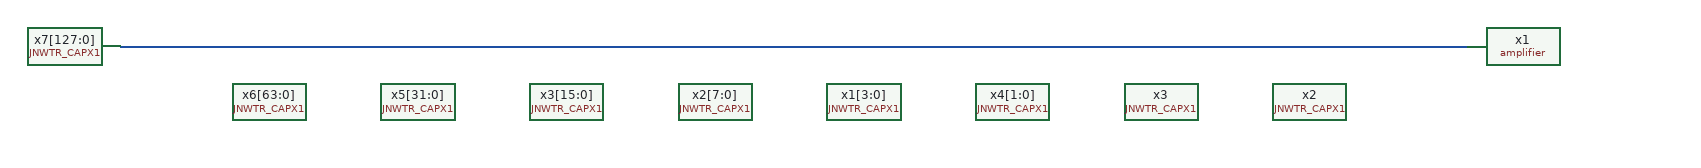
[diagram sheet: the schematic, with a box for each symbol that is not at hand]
v {xschem version=3.4.6 file_version=1.2}
G {}
K {}
V {}
S {}
E {}
N -860 -20 -700 -20 {lab=#net1}
N -700 -20 -540 -20 {lab=#net1}
N -540 -20 -380 -20 {lab=#net1}
N -380 -20 -220 -20 {lab=#net1}
N -220 -20 -60 -20 {lab=#net1}
N -60 -20 110 -20 {lab=#net1}
N -1340 -20 -1180 -20 {lab=#net1}
N -1180 -20 -1020 -20 {lab=#net1}
N -1020 -20 -860 -20 {lab=#net1}
C {JNW_GR07_SKY130A/amplifier.sym} 210 0 2 1 {name=x1}
C {JNW_TR_SKY130A/JNWTR_CAPX1.sym} -60 40 0 0 {name=x2 }
C {JNW_TR_SKY130A/JNWTR_CAPX1.sym} -220 40 0 0 {name=x3 }
C {JNW_TR_SKY130A/JNWTR_CAPX1.sym} -380 40 0 0 {name=x4[1:0]}
C {JNW_TR_SKY130A/JNWTR_CAPX1.sym} -540 40 0 0 {name=x1[3:0]}
C {JNW_TR_SKY130A/JNWTR_CAPX1.sym} -700 40 0 0 {name=x2[7:0]}
C {JNW_TR_SKY130A/JNWTR_CAPX1.sym} -860 40 0 0 {name=x3[15:0]}
C {JNW_TR_SKY130A/JNWTR_CAPX1.sym} -1020 40 0 0 {name=x5[31:0]}
C {JNW_TR_SKY130A/JNWTR_CAPX1.sym} -1180 40 0 0 {name=x6[63:0]}
C {JNW_TR_SKY130A/JNWTR_CAPX1.sym} -1340 40 0 0 {name=x7[127:0]}
